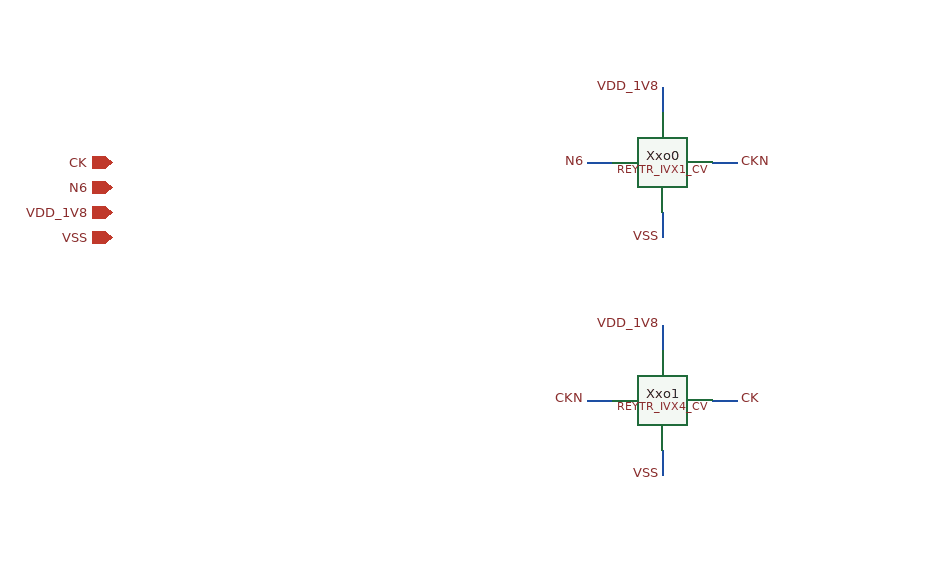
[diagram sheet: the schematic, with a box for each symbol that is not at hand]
v {xschem version=3.0.0 file_version=1.2 }
G {}
K {}
V {}
S {}
E {}
C {devices/iopin.sym} 0 0 0 0 {name=p0 lab=CK}
C {devices/iopin.sym} 0 20 0 0 {name=p1 lab=N6}
C {devices/iopin.sym} 0 40 0 0 {name=p2 lab=VDD_1V8}
C {devices/iopin.sym} 0 60 0 0 {name=p3 lab=VSS}
C {REY_TR_SKY130A/REYTR_IVX1_CV.sym} 400 0 0 0 {name=Xxo0}
N 380.0 0.0 400.0 0.0 {lab=N6}
C {devices/lab_pin.sym} 380.0 0.0 0 0 {name=l0 sig_type=std_logic lab=N6 }
N 500.0 0.0 480.0 0.0 {lab=CKN}
C {devices/lab_pin.sym} 500.0 0.0 2 0 {name=l1 sig_type=std_logic lab=CKN }
N 440.0 -60.0 440.0 -40.0 {lab=VDD_1V8}
C {devices/lab_pin.sym} 440.0 -60.0 3 0 {name=l2 sig_type=std_logic lab=VDD_1V8 }
N 440.0 60.0 440.0 40.0 {lab=VSS}
C {devices/lab_pin.sym} 440.0 60.0 1 0 {name=l3 sig_type=std_logic lab=VSS }
C {REY_TR_SKY130A/REYTR_IVX4_CV.sym} 400 190 0 0 {name=Xxo1}
N 380.0 190.0 400.0 190.0 {lab=CKN}
C {devices/lab_pin.sym} 380.0 190.0 0 0 {name=l4 sig_type=std_logic lab=CKN }
N 500.0 190.0 480.0 190.0 {lab=CK}
C {devices/lab_pin.sym} 500.0 190.0 2 0 {name=l5 sig_type=std_logic lab=CK }
N 440.0 130.0 440.0 150.0 {lab=VDD_1V8}
C {devices/lab_pin.sym} 440.0 130.0 3 0 {name=l6 sig_type=std_logic lab=VDD_1V8 }
N 440.0 250.0 440.0 230.0 {lab=VSS}
C {devices/lab_pin.sym} 440.0 250.0 1 0 {name=l7 sig_type=std_logic lab=VSS }
